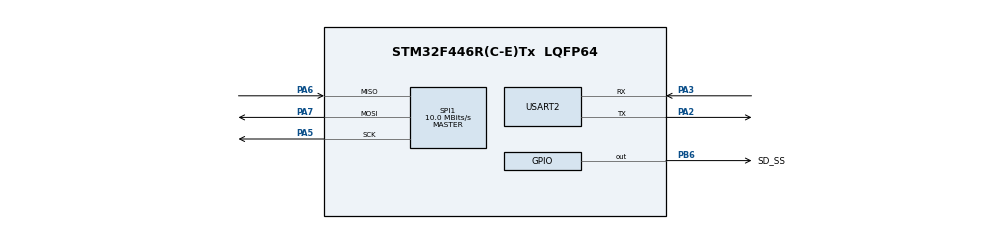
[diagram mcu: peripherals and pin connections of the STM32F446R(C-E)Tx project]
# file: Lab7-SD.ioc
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FATFS._MAX_SS=4096
FATFS._USE_LFN=1
Mcu.Family=STM32F4
Mcu.Name=STM32F446R(C-E)Tx
Mcu.Package=LQFP64
NVIC.PriorityGroup=NVIC_PRIORITYGROUP_4
NVIC.USART2_IRQn=true\:0\:0\:false\:false\:true\:true\:true\:true
PA13.Mode=Serial_Wire
PA13.Signal=SYS_JTMS-SWDIO
PA14.Mode=Serial_Wire
PA14.Signal=SYS_JTCK-SWCLK
PA2.Mode=Asynchronous
PA2.Signal=USART2_TX
PA3.Mode=Asynchronous
PA3.Signal=USART2_RX
PA5.Mode=Full_Duplex_Master
PA5.Signal=SPI1_SCK
PA6.Mode=Full_Duplex_Master
PA6.Signal=SPI1_MISO
PA7.Mode=Full_Duplex_Master
PA7.Signal=SPI1_MOSI
PB6.GPIO_Label=SD_SS
PB6.GPIO_Speed=GPIO_SPEED_FREQ_MEDIUM
PB6.PinState=GPIO_PIN_SET
PB6.Signal=GPIO_Output
PH0-OSC_IN.Mode=HSE-External-Oscillator
PH0-OSC_IN.Signal=RCC_OSC_IN
PH1-OSC_OUT.Mode=HSE-External-Oscillator
PH1-OSC_OUT.Signal=RCC_OSC_OUT
ProjectManager.HeapSize=0x200
ProjectManager.StackSize=0x400
ProjectManager.TargetToolchain=STM32CubeIDE
RCC.AHBFreq_Value=80000000
RCC.APB1CLKDivider=RCC_HCLK_DIV2
RCC.APB1Freq_Value=40000000
RCC.APB1TimFreq_Value=80000000
RCC.APB2Freq_Value=80000000
RCC.APB2TimFreq_Value=80000000
RCC.CortexFreq_Value=80000000
RCC.HCLKFreq_Value=80000000
RCC.PLLM=8
RCC.PLLN=80
RCC.SYSCLKFreq_VALUE=80000000
RCC.SYSCLKSource=RCC_SYSCLKSOURCE_PLLCLK
RCC.USBFreq_Value=80000000
RCC.VCOOutputFreq_Value=160000000
SPI1.BaudRatePrescaler=SPI_BAUDRATEPRESCALER_8
SPI1.CalculateBaudRate=10.0 MBits/s
SPI1.Direction=SPI_DIRECTION_2LINES
SPI1.Mode=SPI_MODE_MASTER
SPI1.VirtualType=VM_MASTER
USART2.VirtualMode=VM_ASYNC
VP_FATFS_VS_Generic.Mode=User_defined
board=custom

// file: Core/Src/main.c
#include "main.h"
#include "fatfs.h"

/* USER CODE BEGIN Includes */
#include "fatfs_sd.h"
#include "string.h"
#include "stdio.h"
/* USER CODE END Includes */

/* USER CODE BEGIN PD */
//SPI_HandleTypeDef hspi1;
FATFS fs;
FATFS *pfs;
FIL fil;
FRESULT fres;
DWORD fre_clust;
uint32_t totalSpace, freeSpace;
char buffer[400];
char user_input;
char menu[] = "Menu:\r\n 1. Estrella\r\n 2. Flor de fuego\r\n 3. Mario\r\n Ingrese opcion: \n";
/* USER CODE END PD */

SPI_HandleTypeDef hspi1;

UART_HandleTypeDef huart2;

void SystemClock_Config(void);
static void MX_GPIO_Init(void);
static void MX_SPI1_Init(void);
static void MX_USART2_UART_Init(void);
void handle_sd_card_operations(const char *filename);
void transmit_uart(char *message);

int main(void)
{

  /* MCU Configuration--------------------------------------------------------*/

  /* Reset of all peripherals, Initializes the Flash interface and the Systick. */
  HAL_Init();

  /* Configure the system clock */
  SystemClock_Config();

  /* Initialize all configured peripherals */
  MX_GPIO_Init();
  MX_SPI1_Init();
  MX_FATFS_Init();
  MX_USART2_UART_Init();

  /* USER CODE BEGIN 2 */
 //handle_sd_card_operations("a.txt");  // Para trabajar con "a.txt"
 // handle_sd_card_operations("b.txt");
  //handle_sd_card_operations("c.txt");
  /* USER CODE END 2 */

  /* Infinite loop */
  while (1)
  {
	  /* Mostrar el menú por UART */
	      transmit_uart(menu);

	      /* Recibir entrada del usuario por UART */
	      HAL_UART_Receive(&huart2, (uint8_t*)&user_input, 1, HAL_MAX_DELAY);

	      /* Procesar la entrada del usuario */
	      switch(user_input) {
	        case '1':
	          transmit_uart("\r\n");
	          //transmit_uart("Mostrando el contenido de a.txt...\r\n");
	          handle_sd_card_operations("estrella_ascii.txt");
	          break;
	        case '2':
	          transmit_uart("\r\n");
	          //transmit_uart("Mostrando el contenido de b.txt...\r\n");
	          handle_sd_card_operations("flor_ascii.txt");
	          break;
	        case '3':
	          transmit_uart("\r\n");
	          //transmit_uart("Mostrando el contenido de c.txt...\r\n");
	          handle_sd_card_operations("mario_ascii.txt");
	          break;
	        default:
	          transmit_uart("Opción no válida. Intente de nuevo.\r\n");
	          break;
	      }

  }
}

void SystemClock_Config(void)
{
  RCC_OscInitTypeDef RCC_OscInitStruct = {0};
  RCC_ClkInitTypeDef RCC_ClkInitStruct = {0};

  /** Configure the main internal regulator output voltage
  */
  __HAL_RCC_PWR_CLK_ENABLE();
  __HAL_PWR_VOLTAGESCALING_CONFIG(PWR_REGULATOR_VOLTAGE_SCALE3);

  /** Initializes the RCC Oscillators according to the specified parameters
  * in the RCC_OscInitTypeDef structure.
  */
  RCC_OscInitStruct.OscillatorType = RCC_OSCILLATORTYPE_HSI;
  RCC_OscInitStruct.HSIState = RCC_HSI_ON;
  RCC_OscInitStruct.HSICalibrationValue = RCC_HSICALIBRATION_DEFAULT;
  RCC_OscInitStruct.PLL.PLLState = RCC_PLL_ON;
  RCC_OscInitStruct.PLL.PLLSource = RCC_PLLSOURCE_HSI;
  RCC_OscInitStruct.PLL.PLLM = 16;
  RCC_OscInitStruct.PLL.PLLN = 336;
  RCC_OscInitStruct.PLL.PLLP = RCC_PLLP_DIV4;
  RCC_OscInitStruct.PLL.PLLQ = 2;
  RCC_OscInitStruct.PLL.PLLR = 2;
  if (HAL_RCC_OscConfig(&RCC_OscInitStruct) != HAL_OK)
  {
    Error_Handler();
  }

  /** Initializes the CPU, AHB and APB buses clocks
  */
  RCC_ClkInitStruct.ClockType = RCC_CLOCKTYPE_HCLK|RCC_CLOCKTYPE_SYSCLK
                              |RCC_CLOCKTYPE_PCLK1|RCC_CLOCKTYPE_PCLK2;
  RCC_ClkInitStruct.SYSCLKSource = RCC_SYSCLKSOURCE_PLLCLK;
  RCC_ClkInitStruct.AHBCLKDivider = RCC_SYSCLK_DIV1;
  RCC_ClkInitStruct.APB1CLKDivider = RCC_HCLK_DIV2;
  RCC_ClkInitStruct.APB2CLKDivider = RCC_HCLK_DIV1;

  if (HAL_RCC_ClockConfig(&RCC_ClkInitStruct, FLASH_LATENCY_2) != HAL_OK)
  {
    Error_Handler();
  }
}

static void MX_SPI1_Init(void)
{

  /* SPI1 parameter configuration*/
  hspi1.Instance = SPI1;
  hspi1.Init.Mode = SPI_MODE_MASTER;
  hspi1.Init.Direction = SPI_DIRECTION_2LINES;
  hspi1.Init.DataSize = SPI_DATASIZE_8BIT;
  hspi1.Init.CLKPolarity = SPI_POLARITY_LOW;
  hspi1.Init.CLKPhase = SPI_PHASE_1EDGE;
  hspi1.Init.NSS = SPI_NSS_SOFT;
  hspi1.Init.BaudRatePrescaler = SPI_BAUDRATEPRESCALER_8;
  hspi1.Init.FirstBit = SPI_FIRSTBIT_MSB;
  hspi1.Init.TIMode = SPI_TIMODE_DISABLE;
  hspi1.Init.CRCCalculation = SPI_CRCCALCULATION_DISABLE;
  hspi1.Init.CRCPolynomial = 10;
  if (HAL_SPI_Init(&hspi1) != HAL_OK)
  {
    Error_Handler();
  }

}

static void MX_USART2_UART_Init(void)
{

  huart2.Instance = USART2;
  huart2.Init.BaudRate = 9600;
  huart2.Init.WordLength = UART_WORDLENGTH_8B;
  huart2.Init.StopBits = UART_STOPBITS_1;
  huart2.Init.Parity = UART_PARITY_NONE;
  huart2.Init.Mode = UART_MODE_TX_RX;
  huart2.Init.HwFlowCtl = UART_HWCONTROL_NONE;
  huart2.Init.OverSampling = UART_OVERSAMPLING_16;
  if (HAL_UART_Init(&huart2) != HAL_OK)
  {
    Error_Handler();
  }

}

static void MX_GPIO_Init(void)
{
  GPIO_InitTypeDef GPIO_InitStruct = {0};

  /* GPIO Ports Clock Enable */
  __HAL_RCC_GPIOH_CLK_ENABLE();
  __HAL_RCC_GPIOA_CLK_ENABLE();
  __HAL_RCC_GPIOB_CLK_ENABLE();

  /*Configure GPIO pin Output Level */
  HAL_GPIO_WritePin(SD_SS_GPIO_Port, SD_SS_Pin, GPIO_PIN_SET);

  /*Configure GPIO pin : SD_SS_Pin */
  GPIO_InitStruct.Pin = SD_SS_Pin;
  GPIO_InitStruct.Mode = GPIO_MODE_OUTPUT_PP;
  GPIO_InitStruct.Pull = GPIO_NOPULL;
  GPIO_InitStruct.Speed = GPIO_SPEED_FREQ_MEDIUM;
  HAL_GPIO_Init(SD_SS_GPIO_Port, &GPIO_InitStruct);

}

/* USER CODE BEGIN 4 */
/* USER CODE BEGIN 4 */

void transmit_uart(char *message) {
    HAL_UART_Transmit(&huart2, (uint8_t*)message, strlen(message), HAL_MAX_DELAY);
}
void handle_sd_card_operations(const char *filename) {
    FRESULT fres;
    HAL_Delay(500); // Retardo para estabilización
    FIL fil;
    char buffer[100];

    // 1. Montar SD
    fres = f_mount(&fs, "/", 0);
    if (fres == FR_OK) {
        //transmit_uart("Micro SD card is mounted successfully!\r\n");
    } else {
        //transmit_uart("Micro SD card's mount error!\r\n");
        return; // Salir si no se puede montar la tarjeta
    }

    // 2. Abrir archivo
    fres = f_open(&fil, filename, FA_OPEN_APPEND | FA_WRITE | FA_READ);
    if (fres == FR_OK) {
        //transmit_uart("File opened for reading.\r\n");
    } else {
        //transmit_uart("File was not opened for reading!\r\n");
        f_mount(NULL, "", 1); // Desmontar SD en caso de error
        return;
    }

 /*/ 3. Leer archivo

    while (f_gets(buffer, sizeof(buffer), &fil)) {
        char mRd[100];
        sprintf(mRd, "%s", buffer);
        transmit_uart(mRd);
    }*/
    // 3.1 Comprobar si el archivo está vacío
    if (f_eof(&fil)) {
        // Si el archivo está vacío, podemos escribir datos iniciales.
        // Mover el puntero del archivo al inicio para preparar la escritura.
        f_lseek(&fil, 0);
    }

    // 3. Leer el archivo línea por línea
    int line_count = 0; // Inicializar un contador para las líneas leídas
    while (f_gets(buffer, sizeof(buffer), &fil)) {
        // Incrementar el contador de líneas por cada línea leída
        line_count++;
        // Declarar un arreglo para formatear la línea leída
        char formatted_line[200];
        // Copiar el contenido del buffer a formatted_line
        sprintf(formatted_line, "%s", buffer);
        // Transmitir la línea formateada a través de UART
        transmit_uart(formatted_line);
        transmit_uart("\r\n");
    }

	/*if (line_count > 0) {
		transmit_uart("Total lines read: ");
		char line_count_str[10];
		sprintf(line_count_str, "%d\r\n", line_count);
		transmit_uart(line_count_str);
	} else {
		transmit_uart("No lines read from file!\r\n");
	}*/

    // 4. Escribir en el archivo (comentar o personalizar según necesidad)
    /* for (uint8_t i = 0; i < 10; i++) {
        f_puts("Hola Mundo.\n", &fil);
    } */

    // 5. Cerrar archivo
    fres = f_close(&fil);
    if (fres == FR_OK) {
        //transmit_uart("The file is closed.\r\n");
    } else {
        //transmit_uart("The file was not closed.\r\n");
    }

    // 6. Desmontar SD
    f_mount(NULL, "", 1);
    if (fres == FR_OK) {
        //transmit_uart("The Micro SD card is unmounted!\r\n");
    } else {
        //transmit_uart("The Micro SD was not unmounted!\r\n");
    }
}

/* USER CODE END 4 */

void Error_Handler(void)
{
  __disable_irq();
  while (1)
  {
  }
}
